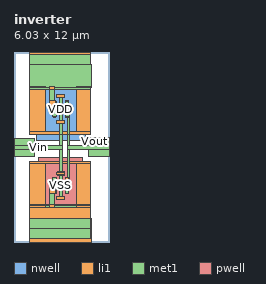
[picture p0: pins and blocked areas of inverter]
MACRO inverter
  CLASS BLOCK ;
  FOREIGN inverter ;
  ORIGIN -1.510 8.140 ;
  SIZE 6.030 BY 12.000 ;
  PIN VDD
    USE POWER ;
    ANTENNADIFFAREA 3.277000 ;
    PORT
      LAYER nwell ;
        RECT 2.930 -1.730 6.010 2.240 ;
      LAYER li1 ;
        RECT 2.500 1.670 6.370 3.860 ;
        RECT 2.500 -1.170 3.500 1.670 ;
        RECT 3.750 0.775 4.050 1.670 ;
        RECT 3.750 0.270 4.160 0.775 ;
        RECT 3.990 -0.265 4.160 0.270 ;
        RECT 5.440 -1.170 6.370 1.670 ;
        RECT 2.500 -1.330 6.370 -1.170 ;
        RECT 3.320 -1.340 5.620 -1.330 ;
      LAYER met1 ;
        RECT 2.500 3.100 6.370 3.700 ;
        RECT 2.500 1.630 6.410 3.100 ;
        RECT 2.500 1.510 6.370 1.630 ;
        RECT 3.750 0.755 4.050 1.510 ;
        RECT 3.750 0.110 4.190 0.755 ;
        RECT 3.960 -0.245 4.190 0.110 ;
    END
  END VDD
  PIN Vin
    ANTENNAGATEAREA 1.000000 ;
    PORT
      LAYER li1 ;
        RECT 4.220 0.990 4.720 1.160 ;
        RECT 4.220 -0.650 4.720 -0.480 ;
        RECT 4.220 -3.890 4.720 -3.720 ;
        RECT 4.220 -5.440 4.720 -5.270 ;
      LAYER met1 ;
        RECT 4.240 0.960 4.700 1.190 ;
        RECT 4.375 -0.450 4.600 0.960 ;
        RECT 4.240 -0.680 4.700 -0.450 ;
        RECT 1.510 -2.070 2.810 -1.600 ;
        RECT 4.375 -2.070 4.600 -0.680 ;
        RECT 1.510 -2.310 4.600 -2.070 ;
        RECT 1.510 -2.770 2.810 -2.310 ;
        RECT 4.375 -3.690 4.600 -2.310 ;
        RECT 4.240 -3.920 4.700 -3.690 ;
        RECT 4.375 -5.240 4.600 -3.920 ;
        RECT 4.240 -5.470 4.700 -5.240 ;
    END
  END Vin
  PIN Vout
    ANTENNADIFFAREA 0.580000 ;
    PORT
      LAYER li1 ;
        RECT 4.780 -0.265 4.950 0.775 ;
        RECT 4.780 -5.100 4.950 -4.060 ;
      LAYER met1 ;
        RECT 4.750 0.330 4.980 0.755 ;
        RECT 4.750 -0.245 5.040 0.330 ;
        RECT 4.860 -2.070 5.040 -0.245 ;
        RECT 6.240 -2.070 7.540 -1.540 ;
        RECT 4.860 -2.310 7.540 -2.070 ;
        RECT 4.860 -4.080 5.040 -2.310 ;
        RECT 6.240 -2.710 7.540 -2.310 ;
        RECT 4.750 -4.750 5.040 -4.080 ;
        RECT 4.750 -5.080 4.980 -4.750 ;
    END
  END Vout
  PIN VSS
    USE POWER ;
    ANTENNADIFFAREA 3.224800 ;
    PORT
      LAYER pwell ;
        RECT 3.080 -6.370 5.860 -2.790 ;
      LAYER li1 ;
        RECT 2.480 -3.200 6.370 -3.030 ;
        RECT 2.480 -5.950 3.490 -3.200 ;
        RECT 3.990 -4.700 4.160 -4.060 ;
        RECT 3.750 -5.100 4.160 -4.700 ;
        RECT 3.750 -5.950 4.050 -5.100 ;
        RECT 5.430 -5.950 6.370 -3.200 ;
        RECT 2.480 -6.670 6.370 -5.950 ;
        RECT 2.470 -8.140 6.380 -6.670 ;
      LAYER met1 ;
        RECT 3.960 -4.500 4.190 -4.080 ;
        RECT 3.750 -5.080 4.190 -4.500 ;
        RECT 3.750 -5.750 4.050 -5.080 ;
        RECT 2.480 -5.830 6.370 -5.750 ;
        RECT 2.460 -7.300 6.370 -5.830 ;
        RECT 2.480 -7.940 6.370 -7.300 ;
    END
  END VSS
END inverter
END LIBRARY

